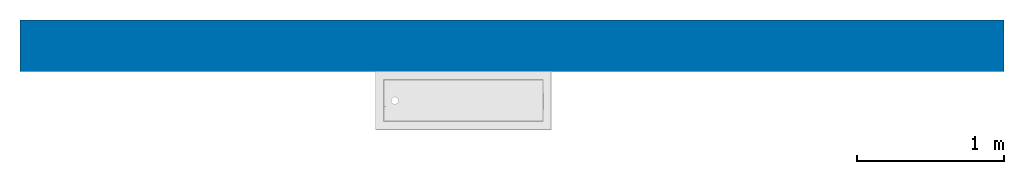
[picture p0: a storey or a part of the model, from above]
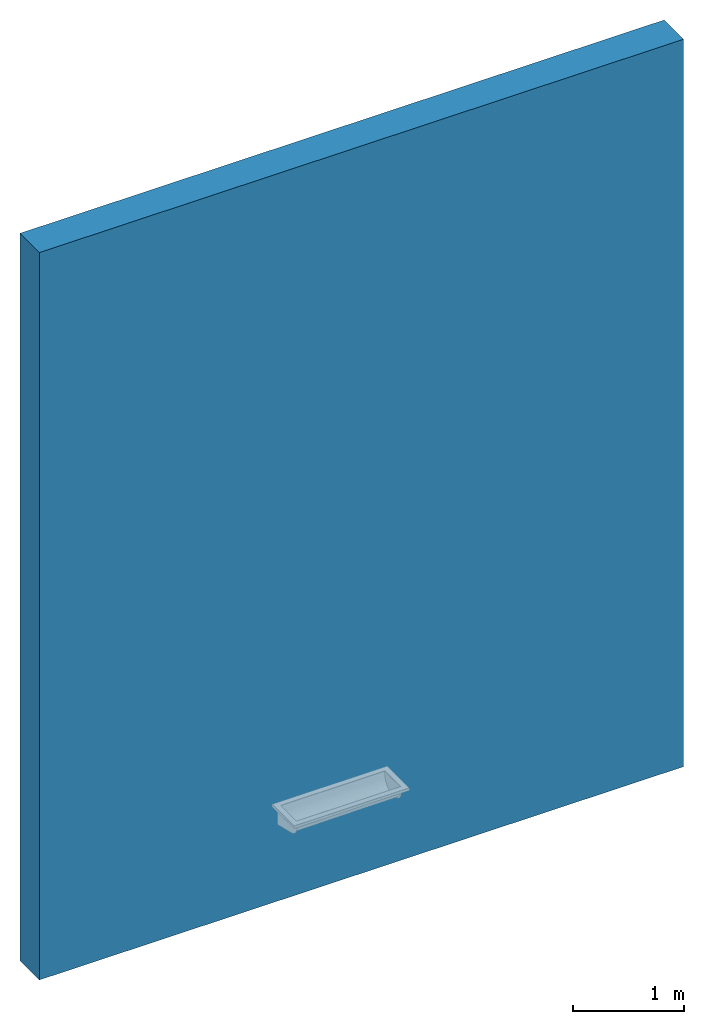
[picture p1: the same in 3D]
Properties of the parts of a building model (IFC2X3)

# File
Description: ViewDefinition [CoordinationView]
File name: Project Number
Time: 2017-01-31T15:30:58
Written by: Autodesk Revit Architecture 2011 - 1.0
Made in: 20100326_1700(x64)

# IfcProject, Project Number
Phase: Project Status

# IfcSite, Default
RefLatitude: 42, 21, 30, 344238; RefLongitude: -71, -3, -35, -194702; RefElevation: 0 mm

# IfcBuilding
Pset_BuildingCommon - NumberOfStoreys: 1
PSet_Revit_Other - Project Issue Date: Issue Date; Project Status: Project Status; Client Name: Owner; Project Address: Enter address here; Project Name: Project Name; Project Number: Project Number

# IfcBuildingStorey, Level 1
Elevation: 0 mm
PSet_Revit_Identity Data - Name: Level 1
PSet_Revit_Constraints - Elevation: 0 mm
PSet_Revit_Type_Graphics - Line Weight: 1; Color: 0; Line Pattern: Centre; Symbol: M_Level Head - Circle; Symbol at End 1 Default: no; Symbol at End 2 Default: yes
PSet_Revit_Type_Constraints - Elevation Base: 0
PSet_Revit_Type_Dimensions - Automatic Room Computation Height: no; Computation Height: 1200 mm

# IfcBuildingElementProxy: Type 1, 120250:Type 1:Type 1:198559
In: Level 1
PSet_Revit_Constraints - Level: Level 1; Elevation: 842.602 mm
PSet_Revit_Mechanical - System Type: Sanitary; System Name: Default Sanitary (Polantis_Production)
PSet_Revit_Identity Data - Mark: 20
PSet_Revit_Phasing - Phase Created: New Construction
PSet_Revit_Type_Data - Weight: 8.4kg
PSet_Revit_Type_Other - WarrantyDurationUnit: 10 years; WarrantyDescription: Any manufacturing defect; SerialNumber: 3456330153393; NominalWidth: 400 mm; NominalLength: 1200 mm; NominalHeight: 180 mm; Name: CANAL wash trough; ModelNumber: 120250; Material: 304 stainless steel; Grade: CE; Finish: Polished satin; Features: Wall-mounted wash trough for 2 services. Bacteriostatic 304 stainless steel. Stainless steel thickness: 1mm for the bowl, 1.5mm for surround and fixing brackets. Easy to install: no joint concealers to install, lightweight wash trough. Drainage on the right. Supplied with 1½" waste. Without overflow. Supplied with brackets and fixing elements. CE marked. Complies with European standard EN 14296. Weight: 8.4kg. Option to add a bacteriostatic 304 stainless steel splashback, stainless steel thickness 1.2mm.
PSet_Revit_Type_General - Version: v1; ProductInformation: http://www.delabie.com/products/120250; ManufacturerURL: http://www.delabie.com; ManufacturerName: DELABIE; Category: Wash troughs
PSet_Revit_Type_Identity Data - URL: http://www.delabie.com; Type Comments: Wall-mounted wash trough; Model: CANAL wash trough; Manufacturer: DELABIE; Description: French manufacturer Delabie is a leader in the European sanitary ware market for non-domestic places. Water controls, solutions for disabled people, sanitary ware, for schools, leisure centres, offices, hospitals, airports…
PSet_Revit_Type_Dimensions - Radius: 24 mm

# IfcWallStandardCase: Basic Wall:Exterior - Brick on Mtl. Stud:397, Basic Wall:Exterior - Brick on Mtl. Stud:184684
In: Level 1
Material: Masonry - Brick 90 mm, Misc. Air Layers - Air Space 76 mm, Wood - Sheathing - plywood 19 mm, Metal - Stud Layer 152 mm, Plasterboard 13 mm
Pset_WallCommon - Reference: Basic Wall:Exterior - Brick on Mtl. Stud; LoadBearing: no; ExtendToStructure: no; IsExternal: yes
PSet_Revit_Constraints - Location Line: 0; Base Constraint: Level 1; Base Offset: 0 mm; Base is Attached: no; Base Extension Distance: 0 mm; Unconnected Height: 8000 mm; Top Offset: 0 mm; Top is Attached: no; Top Extension Distance: 0 mm; Room Bounding: yes; Related to Mass: no
PSet_Revit_Phasing - Phase Created: New Construction
PSet_Revit_Structural - Structural Usage: 0
PSet_Revit_Dimensions - Length: 6700 mm; Area: 53600000 mm2; Volume: 18760000000 mm3
PSet_Revit_Type_Construction - Wrapping at Inserts: 0; Wrapping at Ends: 0; Width: 350 mm; Function: 1
PSet_Revit_Type_Graphics - Coarse Scale Fill Color: 0
